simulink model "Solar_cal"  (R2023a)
settings: Solver=FixedStepAuto  StartTime=0  StopTime=stop_time  FixedStep=step  RelTol=1e-3
InitFcn:
  | Sim_set

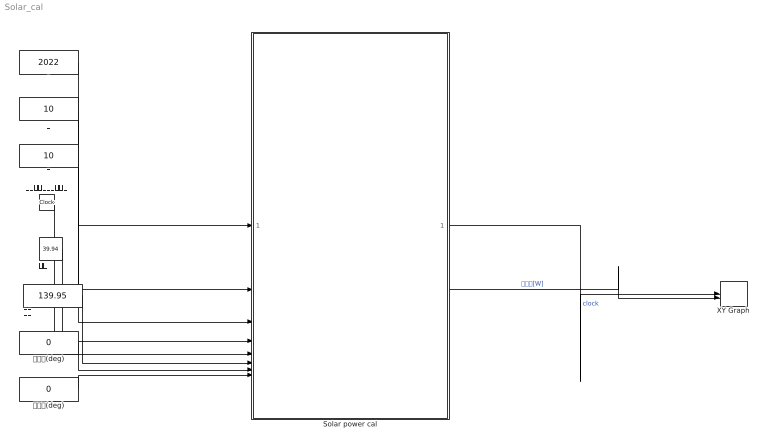
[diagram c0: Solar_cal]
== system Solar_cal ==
  Solar power cal : MATLAB Function  TreatAsAtomicUnit=on
  XY Graph : Record  FileSettingsInternal="{\"entries\":[{\"content\":{\"excelSettings\":{\"content\":{},\"type\":\"Streamout.ExcelSettings\"}},\"type\":\"Streamout.FileSettingStorage\",\"uuid\":\"\"}],\"packageUris\":[\"http:\\/\\/schema.mathworks.com\\/mf0\\/streamout_blocks\\/R2020a\"],\"version\":\"1.0\"}"  Layout=[1 1]  SignalsInternal="{\"entries\":[{\"content\":{\"signals\":[{\"content\":{\"blockPath\":[],\"dimensions\":[1],\"domain\":\"\",\"lineColor\":\"#edb120\",\"plots\":[1],\"port\":1,\"sid\":[\"\"],\"signalID\":551,\"signalName\":\"Solar power cal:1\"},\"type\":\"RecordBlkView.Signal\",\"uuid\":\"\"},{\"content\":{\"blockPath\":[],\"dimensions\":[1],\"domain\":\"\",\"lineColor\":\"#7e2f8e\",\"plots\":[1],\"port\":2,\"sid\":[\"\"],\"signalID\":555,\"signalName\":\"発電量[W]\"},\"type\":\"RecordBlk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"  VisualizationBindings="{\"xyplotplugin\":{\"info\":[{\"series\":[{\"bindingParametersList\":[{\"parameter\":\"X-Axis\",\"signalID\":551,\"signalName\":\"Solar power cal:1\"},{\"parameter\":\"Y-Axis\",\"signalID\":555,\"signalName\":\"発電量[W]\"}],\"seriesID\":32107}],\"subplotID\":1}]}}"  CompatibilityTag=XY
  シミュレーション時間 : Clock
  傾斜角(deg) : Constant  Value=0
  年 : Constant  Value=2022
  方位角(deg) : Constant  Value=0
  日 : Constant  Value=10
  月 : Constant  Value=10
  経度 : Constant  Value=139.95
  緯度 : Constant  Value=39.94
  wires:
  シミュレーション時間/1 -> Solar power cal/4(Time)
  年/1 -> Solar power cal/1(YY)
  月/1 -> Solar power cal/2(MM)
  日/1 -> Solar power cal/3(DD)
  傾斜角(deg)/1 -> Solar power cal/7(b)
  方位角(deg)/1 -> Solar power cal/8(Y)
  緯度/1 -> Solar power cal/5(LON)
  経度/1 -> Solar power cal/6(LAT)
  Solar power cal/2(S_power) -> XY Graph/2  "発電量[W]"
  Solar power cal/1(clock) -> XY Graph/1  "clock"

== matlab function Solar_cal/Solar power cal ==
function [clock,  S_power] = fcn(YY,MM,DD,Time,LON,LAT,b,Y)
%年：YY
%月：MM
%日：DD
%太陽電池傾斜角：b
%斜面の方位角：Y

%太陽定数：J0
J0 = 1367;


%大気透過率：P
P = 0.75;


%太陽電池変換効率：S_effi
S_effi = 0.2;    


%太陽電池面積：As1m^2
As = 1;         


%standard time place(基準時間経度)
STP = 135;        %日本：135、Darwin：142.5


%地面反射率：albedo
albedo = 0.14;  

t1 = datetime(YY,MM,DD);
t2 = datetime(YY,1,1);
dt = t1 - t2;

%年間通し日：dn
dn = days(dt); 


%・太陽赤緯： delta（太陽光線と地球の赤道面との角度、±23°27'の範囲で変化） [単位： 度]
g = ((2*pi()/365));
J = ((dn + 0.5));
delta= 0.33281 - 22.984*cos(g*J) - 0.34990*cos(2*g*J) - 0.13980*cos(3*g*J)+ 3.7872*sin(g*J) + 0.03250*sin(2*g*J) + 0.07187*sin(3*g*J);

%均時差：e
e = 0.0072 * cos( g * J ) - 0.0528*cos( 2*g * J ) - 0.0012*cos(3 * g * J )- 0.1229 * sin( g * J ) - 0.1565*sin( 2*g * J ) - 0.0041*sin(3 * g * J );



%時角： t [単位： 度]
T = (Time/3600) + (LAT - STP)/15 + e; %135=日本(明石)
t = 15 * T - 180;




%太陽高度(仰角)：h
sih = sin(deg2rad(LON))*sin(deg2rad(delta)) + cos(deg2rad(LON))*cos(deg2rad(delta))*cos(deg2rad(t));

h = asin(sih);


%方位角： A（北 = 0, 東 = 90, 南 = 180, 西 = 270°）
sinA = cos(deg2rad (delta)) * sin(deg2rad(t))/cos(h);

cosA = (sin(h) * sin(deg2rad(LON)) - sin(deg2rad(delta))) / cos(h) / cos(deg2rad(LON));

A = atan2(sinA, cosA) + pi;


%法線面直達日射：Jd
if h < 0
    h = 0;
end

    Jd = J0 * P^csc(h);
    %水平面散乱日射数：Js
    Js = J0 * ( 1-P^csc(h) ) * sin( h ) / ( 2 * (1-1.4 * log(P)));

%水平面全天日射：Jh
Jh = Jd * sin(h) + Js;



%傾斜面直達日射：Hd
COSthetaA = sin(h)*cos(deg2rad(b)) + cos(h).*sin(deg2rad(b)).*cos(deg2rad(Y)-A);
COSthetaZ = sin(deg2rad(LON))*sin(deg2rad(delta))+cos(deg2rad(LON))*cos(deg2rad(delta))*cos(deg2rad(g));

Hd = Jd * sin(h) * COSthetaA / COSthetaZ;

%傾斜面散乱日射：Hs
Hs=Js * (1 + cos(deg2rad(b))) / 2;

%傾斜面反射日射：Hr
Hr=Jh * albedo * (1 - cos(deg2rad(b))) / 2;

%傾斜面全天日射
H=Hd+Hs+Hr;


%発電電力量
S_power=H*S_effi*As;
clock = Time/3600;
